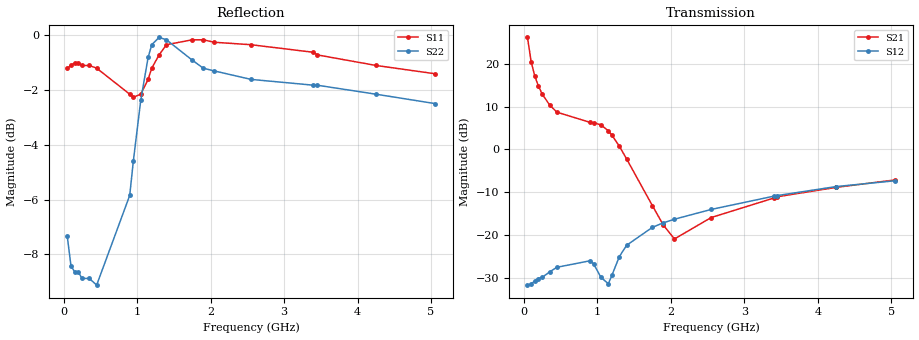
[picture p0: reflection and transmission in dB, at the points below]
!AT-33225
!S-PARAMETERS at Vce=6.0V  Ic=50mA.  LAST UPDATED 08-05-96
# ghz s ma r 50
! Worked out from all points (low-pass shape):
!   101 points, 50 MHz to 5.05 GHz, reference 50 ohm
!   highest |S21| = 26.16 dB at 50 MHz (marker M1); lowest = -20.9 dB at 2.05 GHz (marker M2)
!   |S21| within 3 dB of the highest: start of sweep to 76.46 MHz
!   lowest |S11| = -2.3 dB at 950 MHz (marker M3), VSWR 7.70, Z = 6.53 + j3.44 ohm
!   |S11| at or under -10 dB: nowhere
!   |S22| runs from -9.1 to -0.1 dB; largest |S21 - S12| = 20
!   S11 on the Smith chart (normalised r, x): 50 MHz: 0.07, -0.23; 250 MHz: 0.06, -0.01; 1.9 GHz: 0.01, +0.18; 3.45 GHz: 0.05, +0.37; 5.05 GHz: 0.11, +0.60
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0.05  0.87 -154.0  20.32 103.0  0.026 23.0  0.43 -127.0
0.1  0.88 -168.0  10.58 92.0  0.027 21.0  0.38 -150.0
0.15  0.89 -174.0  7.16 86.0  0.029 24.0  0.37 -159.0
0.2  0.89 -177.0  5.45 81.0  0.031 28.0  0.37 -162.0
0.25  0.88 -179.0  4.44 77.0  0.032 31.0  0.36 -163.0
0.35  0.88 178.0  3.31 69.0  0.037 35.0  0.36 -164.0
0.45  0.87 175.0  2.72 61.0  0.042 38.0  0.35 -162.0
0.9  0.78 171.0  2.07 12.0  0.05 30.0  0.51 -134.0
0.95  0.77 172.0  2.05 3.0  0.046 29.0  0.59 -133.0
1.05  0.78 175.0  1.93 -18.0  0.032 33.0  0.76 -137.0
1.15  0.83 177.0  1.65 -42.0  0.027 72.0  0.91 -147.0
1.2  0.87 177.0  1.46 -53.0  0.034 89.0  0.96 -153.0
1.3  0.92 175.0  1.09 -73.0  0.056 97.0  0.99 -164.0
1.4  0.96 172.0  0.77 -89.0  0.076 94.0  0.98 -172.0
1.75  0.98 163.0  0.22 -133.0  0.123 80.0  0.9 174.0
1.9  0.98 160.0  0.13 -161.0  0.139 77.0  0.87 170.0
2.05  0.97 158.0  0.09 159.0  0.153 73.0  0.86 167.0
2.55  0.96 151.0  0.16 83.0  0.199 64.0  0.83 157.0
3.4  0.93 140.0  0.27 54.0  0.284 51.0  0.81 141.0
3.45  0.92 139.0  0.28 53.0  0.289 50.0  0.81 140.0
4.25  0.88 128.0  0.36 36.0  0.368 34.0  0.78 121.0
5.05  0.85 118.0  0.44 19.0  0.43 19.0  0.75 98.0
